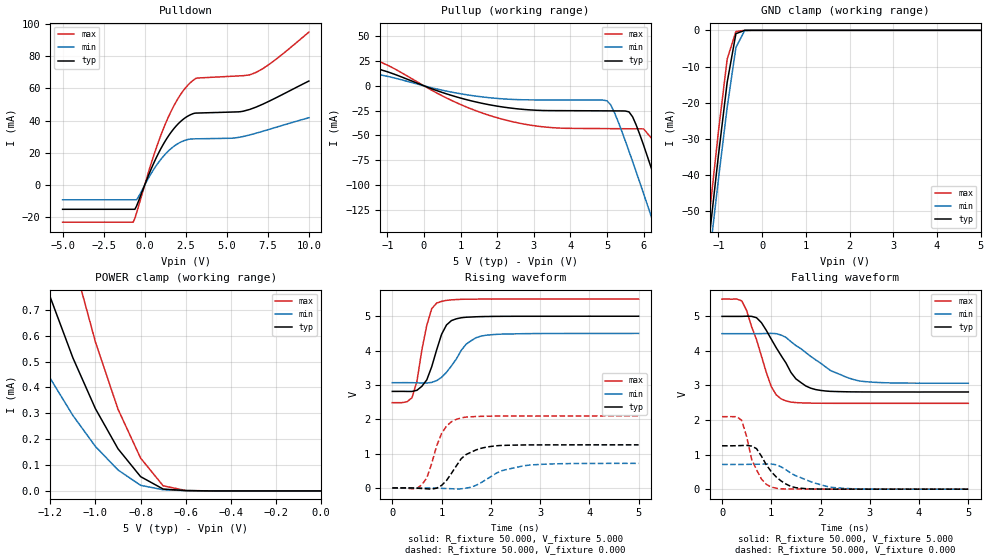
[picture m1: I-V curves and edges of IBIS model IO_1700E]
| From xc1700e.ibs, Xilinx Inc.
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|   Model IO_1700E
[Model]   IO_1700E
Model_type   I/O
Polarity   Non-Inverting
Enable   Active-High
Vinl =   0.800V
Vinh =   2.000V
Vmeas =   2.500V
Cref =  50.000pF
Rref =   1.000M
Vref =  0.000V
C_comp   2.500pF   2.000pF   3.000pF
[Temperature Range]   50.000   100.000   0.000
[Voltage Range]   5.000V   4.500V   5.500V
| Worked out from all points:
|   slope of the pulldown table from 0 to 0.75 V, typ, clamps not added: 41.9 ohm
|   slope of the pullup table from 0 to 0.75 V, typ, clamps not added: 77.4 ohm
|   GND clamp passes 1 mA (typ) near -0.60 V on its own axis
|   POWER clamp passes 1 mA (typ) near -1.29 V on its own axis
|   rising waveform, R_fixture 50.000, V_fixture 5.000: 20-80 % time 306ps typ, 436ps min, 237ps max; typ from 2.81 V to 5 V
|   rising waveform, R_fixture 50.000, V_fixture 0.000: 20-80 % time 427ps typ, 641ps min, 313ps max; typ from 0 V to 1.25 V
|   falling waveform, R_fixture 50.000, V_fixture 5.000: 20-80 % time 556ps typ, 889ps min, 412ps max; typ from 5 V to 2.81 V
|   falling waveform, R_fixture 50.000, V_fixture 0.000: 20-80 % time 410ps typ, 679ps min, 286ps max; typ from 1.25 V to 0 V
[Pulldown]
| voltage   I(typ)   I(min)   I(max)
-5V       -15.06mA   -9.143mA   -23.07mA
-700mV    -15.06mA   -9.143mA   -23.07mA
-600mV    -15.06mA   -9.143mA   -20.71mA
-400mV    -10.6mA    -7.745mA   -14.02mA
400mV     10.11mA    7.282mA    13.59mA
1.1V      24.71mA    17.39mA    33.95mA
1.9V      36.49mA    24.93mA    51.49mA
2.6V      42.63mA    28.2mA     61.69mA
3.2V      44.7mA     28.71mA    66.43mA
5.8V      45.52mA    29.74mA    67.8mA
6.8V      48.47mA    32.23mA    70.01mA
10V       64.58mA    41.79mA    94.97mA
[Pullup]
| voltage   I(typ)   I(min)   I(max)
-5V       34.9mA     19.9mA     58.17mA
-1.8V     22.61mA    15.09mA    33.32mA
800mV     -10.25mA   -6.706mA   -15.55mA
2.1V      -21.13mA   -13.05mA   -33.31mA
5V        -25.32mA   -15.2mA    -43.25mA
5.2V      -25.35mA   -26.7mA    -43.3mA
5.7V      -31.34mA   -76.51mA   -43.44mA
6V        -59.99mA   -109mA     -43.54mA
6.4V      -104mA     -153mA     -61.01mA
6.8V      -150mA     -198mA     -105mA
7.2V      -196mA     -243mA     -153mA
10V       -532mA     -564mA     -503mA
[GND_clamp]
| voltage   I(typ)   I(min)   I(max)
-5V       -506mA     -491mA     -521mA
-1.4V     -78.45mA   -83.45mA   -73.42mA
-1.2V     -56.14mA   -62.01mA   -50.23mA
-1V       -34.51mA   -41.11mA   -27.9mA
-800mV    -14.38mA   -21.28mA   -7.959mA
-600mV    -925uA     -4.729mA   -328uA
-400mV    -3.028uA   -71.54uA   -1.322uA
5V        275pA      251nA      128pA
[POWER_clamp]
| voltage   I(typ)   I(min)   I(max)
-5V       17.89mA    10.61mA    29.1mA
-1.4V     1.31mA     780uA      2.172mA
-1.3V     1.015mA    598uA      1.703mA
-1.2V     749uA      435uA      1.276mA
-1.1V     515uA      292uA      898uA
-1V       318uA      172uA      576uA
-900mV    163uA      81.04uA    316uA
-800mV    55.24uA    21.71uA    127uA
-700mV    7.222uA    4.501uA    19.75uA
-600mV    1.258uA    1.104uA    1.726uA
0V        275pA      2.232nA    167pA
[Ramp]
| variable   typ   min   max
dV/dt_r   0.753/0.437n   0.429/0.638n   1.259/0.300n
dV/dt_f   1.313/0.577n   0.860/0.877n   1.810/0.377n
R_load = 50.000
[Rising Waveform]
R_fixture = 50.000
V_fixture = 5.000
V_fixture_min = 4.500
V_fixture_max = 5.500
L_fixture = 0.000H
C_fixture = 0.000F
| time   V(typ)   V(min)   V(max)
0s        2.811V     3.065V     2.483V
400ps     2.81V      3.065V     2.628V
500ps     2.843V     3.061V     3.103V
700ps     3.147V     3.057V     4.733V
900ps     4.019V     3.124V     5.383V
1ns       4.472V     3.221V     5.433V
1.2ns     4.873V     3.554V     5.477V
1.5ns     4.971V     4.188V     5.496V
1.8ns     4.989V     4.421V     5.499V
5ns       5V         4.5V       5.5V
[Rising Waveform]
R_fixture = 50.000
V_fixture = 0.000
V_fixture_min = 0.000
V_fixture_max = 0.000
L_fixture = 0.000H
C_fixture = 0.000F
| time   V(typ)   V(min)   V(max)
0s        0V         0V         0V
600ps     -16.06mV   329uV      94.02mV
700ps     -25.44mV   -640uV     290mV
1ns       73.02mV    -12.1mV    1.584V
1.2ns     423mV      -23.27mV   1.928V
1.4ns     854mV      -25.78mV   2.043V
1.9ns     1.186V     241mV      2.088V
2.2ns     1.237V     493mV      2.093V
2.7ns     1.252V     650mV      2.094V
5ns       1.255V     715mV      2.098V
[Falling Waveform]
R_fixture = 50.000
V_fixture = 5.000
V_fixture_min = 4.500
V_fixture_max = 5.500
L_fixture = 0.000H
C_fixture = 0.000F
| time   V(typ)   V(min)   V(max)
0s        5V         4.5V       5.5V
400ps     5V         4.499V     5.45V
700ps     4.962V     4.499V     4.329V
1ns       4.341V     4.508V     2.967V
1.2ns     3.866V     4.46V      2.612V
1.5ns     3.192V     4.156V     2.505V
1.9ns     2.882V     3.743V     2.488V
2.2ns     2.83V      3.436V     2.485V
2.8ns     2.814V     3.128V     2.484V
5ns       2.812V     3.066V     2.483V
[Falling Waveform]
R_fixture = 50.000
V_fixture = 0.000
V_fixture_min = 0.000
V_fixture_max = 0.000
L_fixture = 0.000H
C_fixture = 0.000F
| time   V(typ)   V(min)   V(max)
0s        1.255V     715mV      2.098V
300ps     1.257V     715mV      2.097V
400ps     1.262V     715mV      1.99V
500ps     1.267V     717mV      1.522V
600ps     1.247V     719mV      872mV
800ps     955mV      725mV      293mV
1ns       507mV      726mV      60.37mV
1.4ns     77.34mV    460mV      3.525mV
2.2ns     1.045mV    56.85mV    1.322mV
5ns       -24.13uV   30.35uV    -39.58uV
